VERSION 5.8 ;
BUSBITCHARS "[]" ;
DIVIDERCHAR "/" ;
UNITS
    DATABASE MICRONS 1000 ;
END UNITS

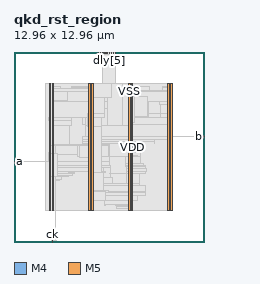
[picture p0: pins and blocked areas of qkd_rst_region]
MACRO qkd_rst_region
  FOREIGN qkd_rst_region 0 0 ;
  CLASS BLOCK ;
  SIZE 12.96 BY 12.96 ;
  PIN a
    DIRECTION INPUT ;
    USE SIGNAL ;
    PORT
      LAYER M4 ;
        RECT  0 5.472 0.084 5.496 ;
    END
  END a
  PIN b
    DIRECTION OUTPUT ;
    USE SIGNAL ;
    PORT
      LAYER M4 ;
        RECT  12.876 7.2 12.96 7.224 ;
    END
  END b
  PIN ck
    DIRECTION INPUT ;
    USE SIGNAL ;
    PORT
      LAYER M5 ;
        RECT  2.592 0 2.616 0.084 ;
    END
  END ck
  PIN dly[0]
    DIRECTION INPUT ;
    USE SIGNAL ;
    PORT
      LAYER M5 ;
        RECT  5.76 12.876 5.784 12.96 ;
    END
  END dly[0]
  PIN dly[1]
    DIRECTION INPUT ;
    USE SIGNAL ;
    PORT
      LAYER M5 ;
        RECT  5.904 12.876 5.928 12.96 ;
    END
  END dly[1]
  PIN dly[2]
    DIRECTION INPUT ;
    USE SIGNAL ;
    PORT
      LAYER M5 ;
        RECT  6.048 12.876 6.072 12.96 ;
    END
  END dly[2]
  PIN dly[3]
    DIRECTION INPUT ;
    USE SIGNAL ;
    PORT
      LAYER M5 ;
        RECT  6.192 12.876 6.216 12.96 ;
    END
  END dly[3]
  PIN dly[4]
    DIRECTION INPUT ;
    USE SIGNAL ;
    PORT
      LAYER M5 ;
        RECT  6.336 12.876 6.36 12.96 ;
    END
  END dly[4]
  PIN dly[5]
    DIRECTION INPUT ;
    USE SIGNAL ;
    PORT
      LAYER M5 ;
        RECT  6.48 12.876 6.504 12.96 ;
    END
  END dly[5]
  PIN dly[6]
    DIRECTION INPUT ;
    USE SIGNAL ;
    PORT
      LAYER M5 ;
        RECT  6.624 12.876 6.648 12.96 ;
    END
  END dly[6]
  PIN dly[7]
    DIRECTION INPUT ;
    USE SIGNAL ;
    PORT
      LAYER M5 ;
        RECT  6.768 12.876 6.792 12.96 ;
    END
  END dly[7]
  PIN por_n
    DIRECTION INPUT ;
    USE SIGNAL ;
    PORT
      LAYER M5 ;
        RECT  6.912 12.876 6.936 12.96 ;
    END
  END por_n
  PIN VDD
    DIRECTION INOUT ;
    USE POWER ;
    PORT
      LAYER M5 ;
        RECT  10.692 2.151 10.812 10.809 ;
        RECT  7.992 2.151 8.112 10.809 ;
        RECT  5.292 2.151 5.412 10.809 ;
        RECT  2.592 2.151 2.712 10.809 ;
    END
  END VDD
  PIN VSS
    DIRECTION INOUT ;
    USE GROUND ;
    PORT
      LAYER M5 ;
        RECT  10.5 2.137 10.62 10.823 ;
        RECT  7.8 2.137 7.92 10.823 ;
        RECT  5.1 2.137 5.22 10.823 ;
        RECT  2.4 2.137 2.52 10.823 ;
    END
  END VSS
  OBS
    LAYER RVTN ;
     RECT  2.16 2.16 10.8 2.295 ;
     RECT  2.16 2.565 10.8 2.835 ;
     RECT  2.16 3.105 10.8 3.375 ;
     RECT  2.16 3.645 10.8 3.915 ;
     RECT  2.16 4.185 10.8 4.455 ;
     RECT  2.16 4.725 10.8 4.995 ;
     RECT  2.16 5.265 10.8 5.535 ;
     RECT  2.16 5.805 10.8 6.075 ;
     RECT  2.16 6.345 10.8 6.615 ;
     RECT  2.16 6.885 10.8 7.155 ;
     RECT  2.16 7.425 10.8 7.695 ;
     RECT  2.16 7.965 10.8 8.235 ;
     RECT  2.16 8.505 10.8 8.775 ;
     RECT  2.16 9.045 10.8 9.315 ;
     RECT  2.16 9.585 10.8 9.855 ;
     RECT  2.16 10.125 10.8 10.395 ;
     RECT  2.16 10.665 10.8 10.8 ;
    LAYER RVTP ;
     RECT  2.16 2.295 10.8 2.565 ;
     RECT  2.16 2.835 10.8 3.105 ;
     RECT  2.16 3.375 10.8 3.645 ;
     RECT  2.16 3.915 10.8 4.185 ;
     RECT  2.16 4.455 10.8 4.725 ;
     RECT  2.16 4.995 10.8 5.265 ;
     RECT  2.16 5.535 10.8 5.805 ;
     RECT  2.16 6.075 10.8 6.345 ;
     RECT  2.16 6.615 10.8 6.885 ;
     RECT  2.16 7.155 10.8 7.425 ;
     RECT  2.16 7.695 10.8 7.965 ;
     RECT  2.16 8.235 10.8 8.505 ;
     RECT  2.16 8.775 10.8 9.045 ;
     RECT  2.16 9.315 10.8 9.585 ;
     RECT  2.16 9.855 10.8 10.125 ;
     RECT  2.16 10.395 10.8 10.665 ;
    LAYER M1 ;
     RECT  2.16 2.151 10.8 10.809 ;
    LAYER M2 ;
     RECT  2.16 2.151 10.8 10.809 ;
     RECT  10.8 2.421 10.812 10.539 ;
     RECT  10.812 7.2 11.435 7.218 ;
    LAYER M3 ;
     RECT  6.984 2.263 7.002 2.299 ;
     RECT  7.815 2.143 7.905 2.299 ;
     RECT  2.415 2.143 2.505 2.413 ;
     RECT  5.115 2.143 5.205 2.413 ;
     RECT  6.984 2.299 7.905 2.413 ;
     RECT  10.515 2.143 10.605 2.413 ;
     RECT  6.984 2.413 8.097 2.497 ;
     RECT  6.192 2.497 6.21 2.533 ;
     RECT  6.948 2.497 8.097 2.533 ;
     RECT  6.192 2.533 8.097 2.803 ;
     RECT  6.192 2.803 8.406 3.181 ;
     RECT  5.115 2.413 5.397 3.379 ;
     RECT  6.192 3.181 8.946 3.379 ;
     RECT  5.115 3.379 8.946 3.437 ;
     RECT  6.12 3.437 8.946 3.839 ;
     RECT  6.12 3.839 8.586 3.983 ;
     RECT  2.415 2.413 2.697 4.225 ;
     RECT  2.415 4.225 3.114 4.261 ;
     RECT  6.12 3.983 6.75 4.415 ;
     RECT  2.415 4.261 3.258 4.459 ;
     RECT  2.415 4.459 3.726 4.531 ;
     RECT  2.415 4.531 3.978 4.657 ;
     RECT  7.704 3.983 8.586 4.657 ;
     RECT  2.415 4.657 4.122 4.801 ;
     RECT  5.115 3.437 5.397 4.801 ;
     RECT  7.704 4.657 8.946 4.801 ;
     RECT  7.704 4.801 9.054 4.991 ;
     RECT  2.415 4.801 5.397 5.071 ;
     RECT  6.12 4.415 6.606 5.071 ;
     RECT  7.704 4.991 8.946 5.161 ;
     RECT  2.415 5.071 6.606 5.189 ;
     RECT  7.596 5.161 8.946 5.189 ;
     RECT  7.596 5.189 8.838 5.369 ;
     RECT  2.415 5.189 6.534 5.467 ;
     RECT  2.304 5.467 6.534 5.504 ;
     RECT  7.596 5.369 8.658 5.803 ;
     RECT  2.34 5.504 6.534 6.071 ;
     RECT  7.416 5.803 8.658 6.115 ;
     RECT  2.415 6.071 6.534 6.151 ;
     RECT  7.308 6.115 8.658 6.151 ;
     RECT  2.415 6.151 8.658 6.683 ;
     RECT  4.68 6.683 8.658 6.691 ;
     RECT  4.68 6.691 8.802 6.853 ;
     RECT  9.576 6.691 9.594 6.853 ;
     RECT  4.68 6.853 9.594 6.961 ;
     RECT  10.515 2.413 10.797 6.961 ;
     RECT  4.68 6.961 10.797 7.187 ;
     RECT  4.896 7.187 10.797 7.189 ;
     RECT  4.896 7.189 11.43 7.229 ;
     RECT  2.415 6.683 3.798 7.933 ;
     RECT  4.896 7.229 10.797 8.041 ;
     RECT  2.415 7.933 3.906 8.311 ;
     RECT  2.376 8.311 3.906 8.473 ;
     RECT  4.68 8.041 10.797 8.473 ;
     RECT  2.376 8.473 10.797 8.501 ;
     RECT  2.376 8.501 9.162 8.525 ;
     RECT  9.972 8.501 10.797 9.391 ;
     RECT  2.415 8.525 9.162 9.553 ;
     RECT  9.9 9.391 10.797 9.553 ;
     RECT  2.415 9.553 10.797 10.253 ;
     RECT  6.192 10.253 10.797 10.319 ;
     RECT  2.415 10.253 5.397 10.463 ;
     RECT  3.888 10.463 5.397 10.547 ;
     RECT  10.116 10.319 10.797 10.547 ;
     RECT  2.415 10.463 3.15 10.589 ;
     RECT  3.888 10.547 5.205 10.589 ;
     RECT  6.192 10.319 9.27 10.589 ;
     RECT  10.116 10.547 10.605 10.589 ;
     RECT  8.856 10.589 8.874 10.625 ;
     RECT  10.26 10.589 10.605 10.625 ;
     RECT  6.192 10.589 8.01 10.769 ;
     RECT  2.415 10.589 2.505 10.817 ;
     RECT  5.115 10.589 5.205 10.817 ;
     RECT  6.192 10.769 7.905 10.817 ;
     RECT  10.515 10.625 10.605 10.817 ;
     RECT  6.192 10.817 7.398 10.829 ;
     RECT  6.3 10.829 6.894 12.029 ;
     RECT  6.876 12.029 6.894 12.845 ;
    LAYER M4 ;
     RECT  0.06 5.472 2.329 5.496 ;
     RECT  2.329 5.472 2.408 6.024 ;
     RECT  2.365 8.496 2.408 8.52 ;
     RECT  2.408 2.148 2.512 10.812 ;
     RECT  2.512 2.418 2.704 10.542 ;
     RECT  2.581 0.096 2.867 0.12 ;
     RECT  2.704 4.512 3.233 4.536 ;
     RECT  2.704 9.648 3.629 10.296 ;
     RECT  3.697 4.704 4.061 4.728 ;
     RECT  2.704 6 4.345 6.6 ;
     RECT  4.345 5.856 4.453 6.6 ;
     RECT  2.704 8.496 4.885 8.52 ;
     RECT  4.885 7.92 4.981 8.52 ;
     RECT  4.453 5.76 5.108 6.6 ;
     RECT  4.981 7.92 5.108 8.76 ;
     RECT  5.108 2.148 5.212 10.812 ;
     RECT  5.212 2.418 5.404 10.542 ;
     RECT  5.749 12.768 5.893 12.792 ;
     RECT  5.404 10.224 6.181 10.542 ;
     RECT  5.404 4.752 6.257 4.776 ;
     RECT  5.404 2.832 6.265 3.48 ;
     RECT  5.893 12.768 6.284 12.84 ;
     RECT  6.284 12 6.371 12.84 ;
     RECT  5.404 7.968 6.397 9.096 ;
     RECT  6.181 10.224 6.397 10.824 ;
     RECT  6.265 3.36 6.437 3.48 ;
     RECT  5.404 5.856 6.469 6.6 ;
     RECT  6.469 5.856 6.505 6.696 ;
     RECT  6.371 12.816 6.905 12.84 ;
     RECT  6.397 7.968 7.409 10.824 ;
     RECT  6.437 3.36 7.808 3.432 ;
     RECT  6.505 4.656 7.808 4.68 ;
     RECT  6.505 5.808 7.808 6.696 ;
     RECT  7.409 7.968 7.808 10.812 ;
     RECT  7.808 2.148 7.912 10.812 ;
     RECT  7.912 2.418 8.104 10.542 ;
     RECT  8.104 8.16 8.237 9.912 ;
     RECT  8.104 5.856 8.417 5.88 ;
     RECT  8.237 8.544 9.137 9.912 ;
     RECT  9.137 8.544 9.173 8.76 ;
     RECT  9.173 8.736 10.508 8.76 ;
     RECT  10.508 2.148 10.612 10.812 ;
     RECT  10.612 2.418 10.804 10.542 ;
     RECT  10.804 7.2 12.924 7.224 ;
    LAYER M5 ;
     RECT  2.592 0.016 2.616 0.085 ;
     RECT  2.592 0.085 2.856 0.131 ;
     RECT  2.832 0.131 2.856 2.137 ;
     RECT  5.1 2.137 5.22 2.151 ;
     RECT  7.8 2.137 7.92 2.151 ;
     RECT  10.5 2.137 10.62 2.151 ;
     RECT  5.1 2.151 5.412 2.821 ;
     RECT  5.1 2.821 6.216 3.443 ;
     RECT  2.4 2.137 2.856 4.501 ;
     RECT  5.1 3.443 5.412 4.741 ;
     RECT  2.4 4.501 2.952 6.035 ;
     RECT  2.4 6.035 2.856 6.611 ;
     RECT  5.1 4.741 5.976 7.909 ;
     RECT  4.992 7.909 5.976 8.485 ;
     RECT  4.992 8.485 6.168 8.771 ;
     RECT  5.1 8.771 6.168 9.829 ;
     RECT  5.1 9.829 6.648 10.789 ;
     RECT  7.8 2.151 8.112 10.789 ;
     RECT  2.4 6.611 2.712 10.809 ;
     RECT  5.1 10.789 8.112 10.809 ;
     RECT  10.5 2.151 10.812 10.809 ;
     RECT  2.4 10.809 2.52 10.823 ;
     RECT  5.1 10.809 7.92 10.823 ;
     RECT  10.5 10.809 10.62 10.823 ;
     RECT  6.048 10.823 6.936 12.757 ;
     RECT  5.76 12.757 6.936 12.944 ;
  END
END qkd_rst_region
END LIBRARY
